# Generated by FakeRAM 2.0
VERSION 5.7 ;
BUSBITCHARS "[]" ;
PROPERTYDEFINITIONS
  MACRO width INTEGER ;
  MACRO depth INTEGER ;
  MACRO banks INTEGER ;
END PROPERTYDEFINITIONS
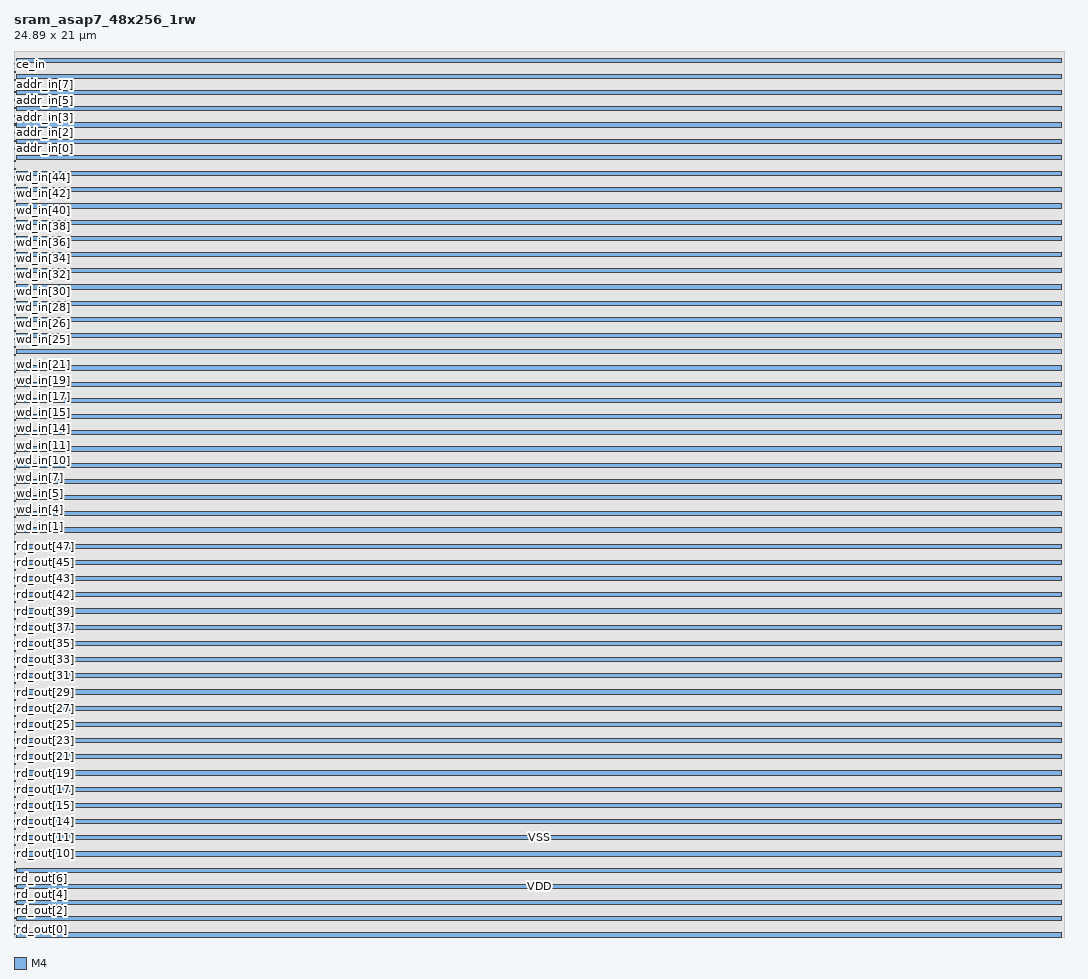
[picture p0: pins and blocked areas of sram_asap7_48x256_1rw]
MACRO sram_asap7_48x256_1rw
  PROPERTY width 48 ;
  PROPERTY depth 256 ;
  PROPERTY banks 4 ;
  FOREIGN sram_asap7_48x256_1rw 0 0 ;
  SYMMETRY X Y R90 ;
  SIZE 24.890 BY 21.000 ;
  CLASS BLOCK ;
  PIN rd_out[0]
    DIRECTION OUTPUT ;
    USE SIGNAL ;
    SHAPE ABUTMENT ;
    PORT
      LAYER M4 ;
      RECT 0.000 0.048 0.024 0.072 ;
    END
  END rd_out[0]
  PIN rd_out[1]
    DIRECTION OUTPUT ;
    USE SIGNAL ;
    SHAPE ABUTMENT ;
    PORT
      LAYER M4 ;
      RECT 0.000 0.240 0.024 0.264 ;
    END
  END rd_out[1]
  PIN rd_out[2]
    DIRECTION OUTPUT ;
    USE SIGNAL ;
    SHAPE ABUTMENT ;
    PORT
      LAYER M4 ;
      RECT 0.000 0.432 0.024 0.456 ;
    END
  END rd_out[2]
  PIN rd_out[3]
    DIRECTION OUTPUT ;
    USE SIGNAL ;
    SHAPE ABUTMENT ;
    PORT
      LAYER M4 ;
      RECT 0.000 0.624 0.024 0.648 ;
    END
  END rd_out[3]
  PIN rd_out[4]
    DIRECTION OUTPUT ;
    USE SIGNAL ;
    SHAPE ABUTMENT ;
    PORT
      LAYER M4 ;
      RECT 0.000 0.816 0.024 0.840 ;
    END
  END rd_out[4]
  PIN rd_out[5]
    DIRECTION OUTPUT ;
    USE SIGNAL ;
    SHAPE ABUTMENT ;
    PORT
      LAYER M4 ;
      RECT 0.000 1.008 0.024 1.032 ;
    END
  END rd_out[5]
  PIN rd_out[6]
    DIRECTION OUTPUT ;
    USE SIGNAL ;
    SHAPE ABUTMENT ;
    PORT
      LAYER M4 ;
      RECT 0.000 1.200 0.024 1.224 ;
    END
  END rd_out[6]
  PIN rd_out[7]
    DIRECTION OUTPUT ;
    USE SIGNAL ;
    SHAPE ABUTMENT ;
    PORT
      LAYER M4 ;
      RECT 0.000 1.392 0.024 1.416 ;
    END
  END rd_out[7]
  PIN rd_out[8]
    DIRECTION OUTPUT ;
    USE SIGNAL ;
    SHAPE ABUTMENT ;
    PORT
      LAYER M4 ;
      RECT 0.000 1.584 0.024 1.608 ;
    END
  END rd_out[8]
  PIN rd_out[9]
    DIRECTION OUTPUT ;
    USE SIGNAL ;
    SHAPE ABUTMENT ;
    PORT
      LAYER M4 ;
      RECT 0.000 1.776 0.024 1.800 ;
    END
  END rd_out[9]
  PIN rd_out[10]
    DIRECTION OUTPUT ;
    USE SIGNAL ;
    SHAPE ABUTMENT ;
    PORT
      LAYER M4 ;
      RECT 0.000 1.968 0.024 1.992 ;
    END
  END rd_out[10]
  PIN rd_out[11]
    DIRECTION OUTPUT ;
    USE SIGNAL ;
    SHAPE ABUTMENT ;
    PORT
      LAYER M4 ;
      RECT 0.000 2.160 0.024 2.184 ;
    END
  END rd_out[11]
  PIN rd_out[12]
    DIRECTION OUTPUT ;
    USE SIGNAL ;
    SHAPE ABUTMENT ;
    PORT
      LAYER M4 ;
      RECT 0.000 2.352 0.024 2.376 ;
    END
  END rd_out[12]
  PIN rd_out[13]
    DIRECTION OUTPUT ;
    USE SIGNAL ;
    SHAPE ABUTMENT ;
    PORT
      LAYER M4 ;
      RECT 0.000 2.544 0.024 2.568 ;
    END
  END rd_out[13]
  PIN rd_out[14]
    DIRECTION OUTPUT ;
    USE SIGNAL ;
    SHAPE ABUTMENT ;
    PORT
      LAYER M4 ;
      RECT 0.000 2.736 0.024 2.760 ;
    END
  END rd_out[14]
  PIN rd_out[15]
    DIRECTION OUTPUT ;
    USE SIGNAL ;
    SHAPE ABUTMENT ;
    PORT
      LAYER M4 ;
      RECT 0.000 2.928 0.024 2.952 ;
    END
  END rd_out[15]
  PIN rd_out[16]
    DIRECTION OUTPUT ;
    USE SIGNAL ;
    SHAPE ABUTMENT ;
    PORT
      LAYER M4 ;
      RECT 0.000 3.120 0.024 3.144 ;
    END
  END rd_out[16]
  PIN rd_out[17]
    DIRECTION OUTPUT ;
    USE SIGNAL ;
    SHAPE ABUTMENT ;
    PORT
      LAYER M4 ;
      RECT 0.000 3.312 0.024 3.336 ;
    END
  END rd_out[17]
  PIN rd_out[18]
    DIRECTION OUTPUT ;
    USE SIGNAL ;
    SHAPE ABUTMENT ;
    PORT
      LAYER M4 ;
      RECT 0.000 3.504 0.024 3.528 ;
    END
  END rd_out[18]
  PIN rd_out[19]
    DIRECTION OUTPUT ;
    USE SIGNAL ;
    SHAPE ABUTMENT ;
    PORT
      LAYER M4 ;
      RECT 0.000 3.696 0.024 3.720 ;
    END
  END rd_out[19]
  PIN rd_out[20]
    DIRECTION OUTPUT ;
    USE SIGNAL ;
    SHAPE ABUTMENT ;
    PORT
      LAYER M4 ;
      RECT 0.000 3.888 0.024 3.912 ;
    END
  END rd_out[20]
  PIN rd_out[21]
    DIRECTION OUTPUT ;
    USE SIGNAL ;
    SHAPE ABUTMENT ;
    PORT
      LAYER M4 ;
      RECT 0.000 4.080 0.024 4.104 ;
    END
  END rd_out[21]
  PIN rd_out[22]
    DIRECTION OUTPUT ;
    USE SIGNAL ;
    SHAPE ABUTMENT ;
    PORT
      LAYER M4 ;
      RECT 0.000 4.272 0.024 4.296 ;
    END
  END rd_out[22]
  PIN rd_out[23]
    DIRECTION OUTPUT ;
    USE SIGNAL ;
    SHAPE ABUTMENT ;
    PORT
      LAYER M4 ;
      RECT 0.000 4.464 0.024 4.488 ;
    END
  END rd_out[23]
  PIN rd_out[24]
    DIRECTION OUTPUT ;
    USE SIGNAL ;
    SHAPE ABUTMENT ;
    PORT
      LAYER M4 ;
      RECT 0.000 4.656 0.024 4.680 ;
    END
  END rd_out[24]
  PIN rd_out[25]
    DIRECTION OUTPUT ;
    USE SIGNAL ;
    SHAPE ABUTMENT ;
    PORT
      LAYER M4 ;
      RECT 0.000 4.848 0.024 4.872 ;
    END
  END rd_out[25]
  PIN rd_out[26]
    DIRECTION OUTPUT ;
    USE SIGNAL ;
    SHAPE ABUTMENT ;
    PORT
      LAYER M4 ;
      RECT 0.000 5.040 0.024 5.064 ;
    END
  END rd_out[26]
  PIN rd_out[27]
    DIRECTION OUTPUT ;
    USE SIGNAL ;
    SHAPE ABUTMENT ;
    PORT
      LAYER M4 ;
      RECT 0.000 5.232 0.024 5.256 ;
    END
  END rd_out[27]
  PIN rd_out[28]
    DIRECTION OUTPUT ;
    USE SIGNAL ;
    SHAPE ABUTMENT ;
    PORT
      LAYER M4 ;
      RECT 0.000 5.424 0.024 5.448 ;
    END
  END rd_out[28]
  PIN rd_out[29]
    DIRECTION OUTPUT ;
    USE SIGNAL ;
    SHAPE ABUTMENT ;
    PORT
      LAYER M4 ;
      RECT 0.000 5.616 0.024 5.640 ;
    END
  END rd_out[29]
  PIN rd_out[30]
    DIRECTION OUTPUT ;
    USE SIGNAL ;
    SHAPE ABUTMENT ;
    PORT
      LAYER M4 ;
      RECT 0.000 5.808 0.024 5.832 ;
    END
  END rd_out[30]
  PIN rd_out[31]
    DIRECTION OUTPUT ;
    USE SIGNAL ;
    SHAPE ABUTMENT ;
    PORT
      LAYER M4 ;
      RECT 0.000 6.000 0.024 6.024 ;
    END
  END rd_out[31]
  PIN rd_out[32]
    DIRECTION OUTPUT ;
    USE SIGNAL ;
    SHAPE ABUTMENT ;
    PORT
      LAYER M4 ;
      RECT 0.000 6.192 0.024 6.216 ;
    END
  END rd_out[32]
  PIN rd_out[33]
    DIRECTION OUTPUT ;
    USE SIGNAL ;
    SHAPE ABUTMENT ;
    PORT
      LAYER M4 ;
      RECT 0.000 6.384 0.024 6.408 ;
    END
  END rd_out[33]
  PIN rd_out[34]
    DIRECTION OUTPUT ;
    USE SIGNAL ;
    SHAPE ABUTMENT ;
    PORT
      LAYER M4 ;
      RECT 0.000 6.576 0.024 6.600 ;
    END
  END rd_out[34]
  PIN rd_out[35]
    DIRECTION OUTPUT ;
    USE SIGNAL ;
    SHAPE ABUTMENT ;
    PORT
      LAYER M4 ;
      RECT 0.000 6.768 0.024 6.792 ;
    END
  END rd_out[35]
  PIN rd_out[36]
    DIRECTION OUTPUT ;
    USE SIGNAL ;
    SHAPE ABUTMENT ;
    PORT
      LAYER M4 ;
      RECT 0.000 6.960 0.024 6.984 ;
    END
  END rd_out[36]
  PIN rd_out[37]
    DIRECTION OUTPUT ;
    USE SIGNAL ;
    SHAPE ABUTMENT ;
    PORT
      LAYER M4 ;
      RECT 0.000 7.152 0.024 7.176 ;
    END
  END rd_out[37]
  PIN rd_out[38]
    DIRECTION OUTPUT ;
    USE SIGNAL ;
    SHAPE ABUTMENT ;
    PORT
      LAYER M4 ;
      RECT 0.000 7.344 0.024 7.368 ;
    END
  END rd_out[38]
  PIN rd_out[39]
    DIRECTION OUTPUT ;
    USE SIGNAL ;
    SHAPE ABUTMENT ;
    PORT
      LAYER M4 ;
      RECT 0.000 7.536 0.024 7.560 ;
    END
  END rd_out[39]
  PIN rd_out[40]
    DIRECTION OUTPUT ;
    USE SIGNAL ;
    SHAPE ABUTMENT ;
    PORT
      LAYER M4 ;
      RECT 0.000 7.728 0.024 7.752 ;
    END
  END rd_out[40]
  PIN rd_out[41]
    DIRECTION OUTPUT ;
    USE SIGNAL ;
    SHAPE ABUTMENT ;
    PORT
      LAYER M4 ;
      RECT 0.000 7.920 0.024 7.944 ;
    END
  END rd_out[41]
  PIN rd_out[42]
    DIRECTION OUTPUT ;
    USE SIGNAL ;
    SHAPE ABUTMENT ;
    PORT
      LAYER M4 ;
      RECT 0.000 8.112 0.024 8.136 ;
    END
  END rd_out[42]
  PIN rd_out[43]
    DIRECTION OUTPUT ;
    USE SIGNAL ;
    SHAPE ABUTMENT ;
    PORT
      LAYER M4 ;
      RECT 0.000 8.304 0.024 8.328 ;
    END
  END rd_out[43]
  PIN rd_out[44]
    DIRECTION OUTPUT ;
    USE SIGNAL ;
    SHAPE ABUTMENT ;
    PORT
      LAYER M4 ;
      RECT 0.000 8.496 0.024 8.520 ;
    END
  END rd_out[44]
  PIN rd_out[45]
    DIRECTION OUTPUT ;
    USE SIGNAL ;
    SHAPE ABUTMENT ;
    PORT
      LAYER M4 ;
      RECT 0.000 8.688 0.024 8.712 ;
    END
  END rd_out[45]
  PIN rd_out[46]
    DIRECTION OUTPUT ;
    USE SIGNAL ;
    SHAPE ABUTMENT ;
    PORT
      LAYER M4 ;
      RECT 0.000 8.880 0.024 8.904 ;
    END
  END rd_out[46]
  PIN rd_out[47]
    DIRECTION OUTPUT ;
    USE SIGNAL ;
    SHAPE ABUTMENT ;
    PORT
      LAYER M4 ;
      RECT 0.000 9.072 0.024 9.096 ;
    END
  END rd_out[47]
  PIN wd_in[0]
    DIRECTION INPUT ;
    USE SIGNAL ;
    SHAPE ABUTMENT ;
    PORT
      LAYER M4 ;
      RECT 0.000 9.360 0.024 9.384 ;
    END
  END wd_in[0]
  PIN wd_in[1]
    DIRECTION INPUT ;
    USE SIGNAL ;
    SHAPE ABUTMENT ;
    PORT
      LAYER M4 ;
      RECT 0.000 9.552 0.024 9.576 ;
    END
  END wd_in[1]
  PIN wd_in[2]
    DIRECTION INPUT ;
    USE SIGNAL ;
    SHAPE ABUTMENT ;
    PORT
      LAYER M4 ;
      RECT 0.000 9.744 0.024 9.768 ;
    END
  END wd_in[2]
  PIN wd_in[3]
    DIRECTION INPUT ;
    USE SIGNAL ;
    SHAPE ABUTMENT ;
    PORT
      LAYER M4 ;
      RECT 0.000 9.936 0.024 9.960 ;
    END
  END wd_in[3]
  PIN wd_in[4]
    DIRECTION INPUT ;
    USE SIGNAL ;
    SHAPE ABUTMENT ;
    PORT
      LAYER M4 ;
      RECT 0.000 10.128 0.024 10.152 ;
    END
  END wd_in[4]
  PIN wd_in[5]
    DIRECTION INPUT ;
    USE SIGNAL ;
    SHAPE ABUTMENT ;
    PORT
      LAYER M4 ;
      RECT 0.000 10.320 0.024 10.344 ;
    END
  END wd_in[5]
  PIN wd_in[6]
    DIRECTION INPUT ;
    USE SIGNAL ;
    SHAPE ABUTMENT ;
    PORT
      LAYER M4 ;
      RECT 0.000 10.512 0.024 10.536 ;
    END
  END wd_in[6]
  PIN wd_in[7]
    DIRECTION INPUT ;
    USE SIGNAL ;
    SHAPE ABUTMENT ;
    PORT
      LAYER M4 ;
      RECT 0.000 10.704 0.024 10.728 ;
    END
  END wd_in[7]
  PIN wd_in[8]
    DIRECTION INPUT ;
    USE SIGNAL ;
    SHAPE ABUTMENT ;
    PORT
      LAYER M4 ;
      RECT 0.000 10.896 0.024 10.920 ;
    END
  END wd_in[8]
  PIN wd_in[9]
    DIRECTION INPUT ;
    USE SIGNAL ;
    SHAPE ABUTMENT ;
    PORT
      LAYER M4 ;
      RECT 0.000 11.088 0.024 11.112 ;
    END
  END wd_in[9]
  PIN wd_in[10]
    DIRECTION INPUT ;
    USE SIGNAL ;
    SHAPE ABUTMENT ;
    PORT
      LAYER M4 ;
      RECT 0.000 11.280 0.024 11.304 ;
    END
  END wd_in[10]
  PIN wd_in[11]
    DIRECTION INPUT ;
    USE SIGNAL ;
    SHAPE ABUTMENT ;
    PORT
      LAYER M4 ;
      RECT 0.000 11.472 0.024 11.496 ;
    END
  END wd_in[11]
  PIN wd_in[12]
    DIRECTION INPUT ;
    USE SIGNAL ;
    SHAPE ABUTMENT ;
    PORT
      LAYER M4 ;
      RECT 0.000 11.664 0.024 11.688 ;
    END
  END wd_in[12]
  PIN wd_in[13]
    DIRECTION INPUT ;
    USE SIGNAL ;
    SHAPE ABUTMENT ;
    PORT
      LAYER M4 ;
      RECT 0.000 11.856 0.024 11.880 ;
    END
  END wd_in[13]
  PIN wd_in[14]
    DIRECTION INPUT ;
    USE SIGNAL ;
    SHAPE ABUTMENT ;
    PORT
      LAYER M4 ;
      RECT 0.000 12.048 0.024 12.072 ;
    END
  END wd_in[14]
  PIN wd_in[15]
    DIRECTION INPUT ;
    USE SIGNAL ;
    SHAPE ABUTMENT ;
    PORT
      LAYER M4 ;
      RECT 0.000 12.240 0.024 12.264 ;
    END
  END wd_in[15]
  PIN wd_in[16]
    DIRECTION INPUT ;
    USE SIGNAL ;
    SHAPE ABUTMENT ;
    PORT
      LAYER M4 ;
      RECT 0.000 12.432 0.024 12.456 ;
    END
  END wd_in[16]
  PIN wd_in[17]
    DIRECTION INPUT ;
    USE SIGNAL ;
    SHAPE ABUTMENT ;
    PORT
      LAYER M4 ;
      RECT 0.000 12.624 0.024 12.648 ;
    END
  END wd_in[17]
  PIN wd_in[18]
    DIRECTION INPUT ;
    USE SIGNAL ;
    SHAPE ABUTMENT ;
    PORT
      LAYER M4 ;
      RECT 0.000 12.816 0.024 12.840 ;
    END
  END wd_in[18]
  PIN wd_in[19]
    DIRECTION INPUT ;
    USE SIGNAL ;
    SHAPE ABUTMENT ;
    PORT
      LAYER M4 ;
      RECT 0.000 13.008 0.024 13.032 ;
    END
  END wd_in[19]
  PIN wd_in[20]
    DIRECTION INPUT ;
    USE SIGNAL ;
    SHAPE ABUTMENT ;
    PORT
      LAYER M4 ;
      RECT 0.000 13.200 0.024 13.224 ;
    END
  END wd_in[20]
  PIN wd_in[21]
    DIRECTION INPUT ;
    USE SIGNAL ;
    SHAPE ABUTMENT ;
    PORT
      LAYER M4 ;
      RECT 0.000 13.392 0.024 13.416 ;
    END
  END wd_in[21]
  PIN wd_in[22]
    DIRECTION INPUT ;
    USE SIGNAL ;
    SHAPE ABUTMENT ;
    PORT
      LAYER M4 ;
      RECT 0.000 13.584 0.024 13.608 ;
    END
  END wd_in[22]
  PIN wd_in[23]
    DIRECTION INPUT ;
    USE SIGNAL ;
    SHAPE ABUTMENT ;
    PORT
      LAYER M4 ;
      RECT 0.000 13.776 0.024 13.800 ;
    END
  END wd_in[23]
  PIN wd_in[24]
    DIRECTION INPUT ;
    USE SIGNAL ;
    SHAPE ABUTMENT ;
    PORT
      LAYER M4 ;
      RECT 0.000 13.968 0.024 13.992 ;
    END
  END wd_in[24]
  PIN wd_in[25]
    DIRECTION INPUT ;
    USE SIGNAL ;
    SHAPE ABUTMENT ;
    PORT
      LAYER M4 ;
      RECT 0.000 14.160 0.024 14.184 ;
    END
  END wd_in[25]
  PIN wd_in[26]
    DIRECTION INPUT ;
    USE SIGNAL ;
    SHAPE ABUTMENT ;
    PORT
      LAYER M4 ;
      RECT 0.000 14.352 0.024 14.376 ;
    END
  END wd_in[26]
  PIN wd_in[27]
    DIRECTION INPUT ;
    USE SIGNAL ;
    SHAPE ABUTMENT ;
    PORT
      LAYER M4 ;
      RECT 0.000 14.544 0.024 14.568 ;
    END
  END wd_in[27]
  PIN wd_in[28]
    DIRECTION INPUT ;
    USE SIGNAL ;
    SHAPE ABUTMENT ;
    PORT
      LAYER M4 ;
      RECT 0.000 14.736 0.024 14.760 ;
    END
  END wd_in[28]
  PIN wd_in[29]
    DIRECTION INPUT ;
    USE SIGNAL ;
    SHAPE ABUTMENT ;
    PORT
      LAYER M4 ;
      RECT 0.000 14.928 0.024 14.952 ;
    END
  END wd_in[29]
  PIN wd_in[30]
    DIRECTION INPUT ;
    USE SIGNAL ;
    SHAPE ABUTMENT ;
    PORT
      LAYER M4 ;
      RECT 0.000 15.120 0.024 15.144 ;
    END
  END wd_in[30]
  PIN wd_in[31]
    DIRECTION INPUT ;
    USE SIGNAL ;
    SHAPE ABUTMENT ;
    PORT
      LAYER M4 ;
      RECT 0.000 15.312 0.024 15.336 ;
    END
  END wd_in[31]
  PIN wd_in[32]
    DIRECTION INPUT ;
    USE SIGNAL ;
    SHAPE ABUTMENT ;
    PORT
      LAYER M4 ;
      RECT 0.000 15.504 0.024 15.528 ;
    END
  END wd_in[32]
  PIN wd_in[33]
    DIRECTION INPUT ;
    USE SIGNAL ;
    SHAPE ABUTMENT ;
    PORT
      LAYER M4 ;
      RECT 0.000 15.696 0.024 15.720 ;
    END
  END wd_in[33]
  PIN wd_in[34]
    DIRECTION INPUT ;
    USE SIGNAL ;
    SHAPE ABUTMENT ;
    PORT
      LAYER M4 ;
      RECT 0.000 15.888 0.024 15.912 ;
    END
  END wd_in[34]
  PIN wd_in[35]
    DIRECTION INPUT ;
    USE SIGNAL ;
    SHAPE ABUTMENT ;
    PORT
      LAYER M4 ;
      RECT 0.000 16.080 0.024 16.104 ;
    END
  END wd_in[35]
  PIN wd_in[36]
    DIRECTION INPUT ;
    USE SIGNAL ;
    SHAPE ABUTMENT ;
    PORT
      LAYER M4 ;
      RECT 0.000 16.272 0.024 16.296 ;
    END
  END wd_in[36]
  PIN wd_in[37]
    DIRECTION INPUT ;
    USE SIGNAL ;
    SHAPE ABUTMENT ;
    PORT
      LAYER M4 ;
      RECT 0.000 16.464 0.024 16.488 ;
    END
  END wd_in[37]
  PIN wd_in[38]
    DIRECTION INPUT ;
    USE SIGNAL ;
    SHAPE ABUTMENT ;
    PORT
      LAYER M4 ;
      RECT 0.000 16.656 0.024 16.680 ;
    END
  END wd_in[38]
  PIN wd_in[39]
    DIRECTION INPUT ;
    USE SIGNAL ;
    SHAPE ABUTMENT ;
    PORT
      LAYER M4 ;
      RECT 0.000 16.848 0.024 16.872 ;
    END
  END wd_in[39]
  PIN wd_in[40]
    DIRECTION INPUT ;
    USE SIGNAL ;
    SHAPE ABUTMENT ;
    PORT
      LAYER M4 ;
      RECT 0.000 17.040 0.024 17.064 ;
    END
  END wd_in[40]
  PIN wd_in[41]
    DIRECTION INPUT ;
    USE SIGNAL ;
    SHAPE ABUTMENT ;
    PORT
      LAYER M4 ;
      RECT 0.000 17.232 0.024 17.256 ;
    END
  END wd_in[41]
  PIN wd_in[42]
    DIRECTION INPUT ;
    USE SIGNAL ;
    SHAPE ABUTMENT ;
    PORT
      LAYER M4 ;
      RECT 0.000 17.424 0.024 17.448 ;
    END
  END wd_in[42]
  PIN wd_in[43]
    DIRECTION INPUT ;
    USE SIGNAL ;
    SHAPE ABUTMENT ;
    PORT
      LAYER M4 ;
      RECT 0.000 17.616 0.024 17.640 ;
    END
  END wd_in[43]
  PIN wd_in[44]
    DIRECTION INPUT ;
    USE SIGNAL ;
    SHAPE ABUTMENT ;
    PORT
      LAYER M4 ;
      RECT 0.000 17.808 0.024 17.832 ;
    END
  END wd_in[44]
  PIN wd_in[45]
    DIRECTION INPUT ;
    USE SIGNAL ;
    SHAPE ABUTMENT ;
    PORT
      LAYER M4 ;
      RECT 0.000 18.000 0.024 18.024 ;
    END
  END wd_in[45]
  PIN wd_in[46]
    DIRECTION INPUT ;
    USE SIGNAL ;
    SHAPE ABUTMENT ;
    PORT
      LAYER M4 ;
      RECT 0.000 18.192 0.024 18.216 ;
    END
  END wd_in[46]
  PIN wd_in[47]
    DIRECTION INPUT ;
    USE SIGNAL ;
    SHAPE ABUTMENT ;
    PORT
      LAYER M4 ;
      RECT 0.000 18.384 0.024 18.408 ;
    END
  END wd_in[47]
  PIN addr_in[0]
    DIRECTION INPUT ;
    USE SIGNAL ;
    SHAPE ABUTMENT ;
    PORT
      LAYER M4 ;
      RECT 0.000 18.672 0.024 18.696 ;
    END
  END addr_in[0]
  PIN addr_in[1]
    DIRECTION INPUT ;
    USE SIGNAL ;
    SHAPE ABUTMENT ;
    PORT
      LAYER M4 ;
      RECT 0.000 18.864 0.024 18.888 ;
    END
  END addr_in[1]
  PIN addr_in[2]
    DIRECTION INPUT ;
    USE SIGNAL ;
    SHAPE ABUTMENT ;
    PORT
      LAYER M4 ;
      RECT 0.000 19.056 0.024 19.080 ;
    END
  END addr_in[2]
  PIN addr_in[3]
    DIRECTION INPUT ;
    USE SIGNAL ;
    SHAPE ABUTMENT ;
    PORT
      LAYER M4 ;
      RECT 0.000 19.248 0.024 19.272 ;
    END
  END addr_in[3]
  PIN addr_in[4]
    DIRECTION INPUT ;
    USE SIGNAL ;
    SHAPE ABUTMENT ;
    PORT
      LAYER M4 ;
      RECT 0.000 19.440 0.024 19.464 ;
    END
  END addr_in[4]
  PIN addr_in[5]
    DIRECTION INPUT ;
    USE SIGNAL ;
    SHAPE ABUTMENT ;
    PORT
      LAYER M4 ;
      RECT 0.000 19.632 0.024 19.656 ;
    END
  END addr_in[5]
  PIN addr_in[6]
    DIRECTION INPUT ;
    USE SIGNAL ;
    SHAPE ABUTMENT ;
    PORT
      LAYER M4 ;
      RECT 0.000 19.824 0.024 19.848 ;
    END
  END addr_in[6]
  PIN addr_in[7]
    DIRECTION INPUT ;
    USE SIGNAL ;
    SHAPE ABUTMENT ;
    PORT
      LAYER M4 ;
      RECT 0.000 20.016 0.024 20.040 ;
    END
  END addr_in[7]
  PIN we_in
    DIRECTION INPUT ;
    USE SIGNAL ;
    SHAPE ABUTMENT ;
    PORT
      LAYER M4 ;
      RECT 0.000 20.304 0.024 20.328 ;
    END
  END we_in
  PIN ce_in
    DIRECTION INPUT ;
    USE SIGNAL ;
    SHAPE ABUTMENT ;
    PORT
      LAYER M4 ;
      RECT 0.000 20.496 0.024 20.520 ;
    END
  END ce_in
  PIN clk
    DIRECTION INPUT ;
    USE SIGNAL ;
    SHAPE ABUTMENT ;
    PORT
      LAYER M4 ;
      RECT 0.000 20.688 0.024 20.712 ;
    END
  END clk
  PIN VSS
    DIRECTION INOUT ;
    USE GROUND ;
    PORT
      LAYER M4 ;
      RECT 0.048 0.000 24.842 0.096 ;
      RECT 0.048 0.768 24.842 0.864 ;
      RECT 0.048 1.536 24.842 1.632 ;
      RECT 0.048 2.304 24.842 2.400 ;
      RECT 0.048 3.072 24.842 3.168 ;
      RECT 0.048 3.840 24.842 3.936 ;
      RECT 0.048 4.608 24.842 4.704 ;
      RECT 0.048 5.376 24.842 5.472 ;
      RECT 0.048 6.144 24.842 6.240 ;
      RECT 0.048 6.912 24.842 7.008 ;
      RECT 0.048 7.680 24.842 7.776 ;
      RECT 0.048 8.448 24.842 8.544 ;
      RECT 0.048 9.216 24.842 9.312 ;
      RECT 0.048 9.984 24.842 10.080 ;
      RECT 0.048 10.752 24.842 10.848 ;
      RECT 0.048 11.520 24.842 11.616 ;
      RECT 0.048 12.288 24.842 12.384 ;
      RECT 0.048 13.056 24.842 13.152 ;
      RECT 0.048 13.824 24.842 13.920 ;
      RECT 0.048 14.592 24.842 14.688 ;
      RECT 0.048 15.360 24.842 15.456 ;
      RECT 0.048 16.128 24.842 16.224 ;
      RECT 0.048 16.896 24.842 16.992 ;
      RECT 0.048 17.664 24.842 17.760 ;
      RECT 0.048 18.432 24.842 18.528 ;
      RECT 0.048 19.200 24.842 19.296 ;
      RECT 0.048 19.968 24.842 20.064 ;
      RECT 0.048 20.736 24.842 20.832 ;
    END
  END VSS
  PIN VDD
    DIRECTION INOUT ;
    USE POWER ;
    PORT
      LAYER M4 ;
      RECT 0.048 0.384 24.842 0.480 ;
      RECT 0.048 1.152 24.842 1.248 ;
      RECT 0.048 1.920 24.842 2.016 ;
      RECT 0.048 2.688 24.842 2.784 ;
      RECT 0.048 3.456 24.842 3.552 ;
      RECT 0.048 4.224 24.842 4.320 ;
      RECT 0.048 4.992 24.842 5.088 ;
      RECT 0.048 5.760 24.842 5.856 ;
      RECT 0.048 6.528 24.842 6.624 ;
      RECT 0.048 7.296 24.842 7.392 ;
      RECT 0.048 8.064 24.842 8.160 ;
      RECT 0.048 8.832 24.842 8.928 ;
      RECT 0.048 9.600 24.842 9.696 ;
      RECT 0.048 10.368 24.842 10.464 ;
      RECT 0.048 11.136 24.842 11.232 ;
      RECT 0.048 11.904 24.842 12.000 ;
      RECT 0.048 12.672 24.842 12.768 ;
      RECT 0.048 13.440 24.842 13.536 ;
      RECT 0.048 14.208 24.842 14.304 ;
      RECT 0.048 14.976 24.842 15.072 ;
      RECT 0.048 15.744 24.842 15.840 ;
      RECT 0.048 16.512 24.842 16.608 ;
      RECT 0.048 17.280 24.842 17.376 ;
      RECT 0.048 18.048 24.842 18.144 ;
      RECT 0.048 18.816 24.842 18.912 ;
      RECT 0.048 19.584 24.842 19.680 ;
      RECT 0.048 20.352 24.842 20.448 ;
    END
  END VDD
  OBS
    LAYER M1 ;
    RECT 0 0 24.890 21.000 ;
    LAYER M2 ;
    RECT 0 0 24.890 21.000 ;
    LAYER M3 ;
    RECT 0 0 24.890 21.000 ;
    LAYER M4 ;
    RECT 0 0 24.890 21.000 ;
  END
END sram_asap7_48x256_1rw

END LIBRARY
